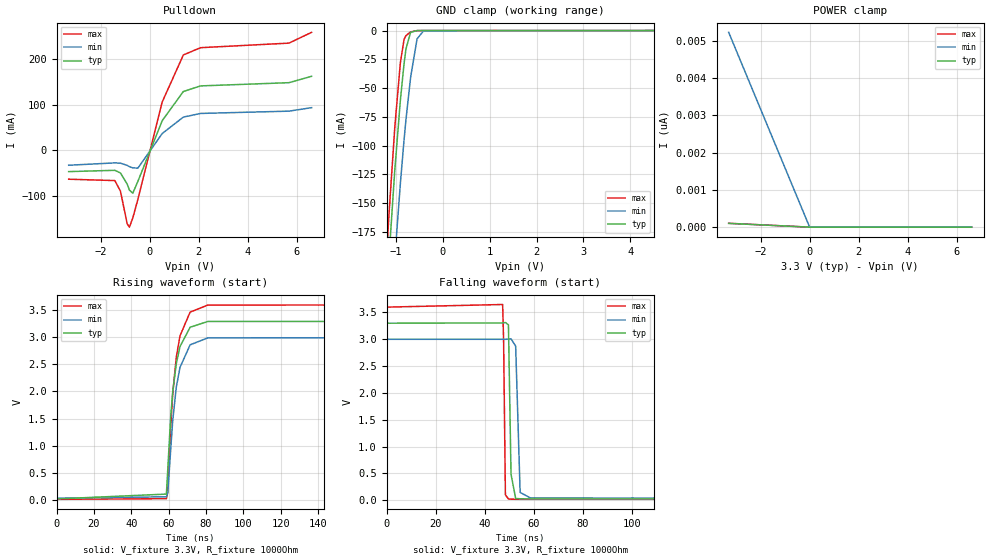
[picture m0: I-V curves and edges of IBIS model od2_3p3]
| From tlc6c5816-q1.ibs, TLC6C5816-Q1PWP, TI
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|   od2_3p3 Model
[Model]   od2_3p3
Model_type   Open_drain
Polarity   Inverting
Vmeas = 1.65
Vref = 3.3
Cref = 2pF
Rref = 1000
|   typ   min   max
C_comp   1.810pF   1.752pF   1.861pF
|  Where Nom  PVT is Nominal Process, 3.3V,  27C
|   Fast PVT is Strong Process,  3.6V, -40C
|   Slow PVT is Weak Process,   3.0V, 150C
[Voltage Range]   3.3   3   3.6
|Junction Temperature
[Temperature Range]   27   150   -40
[Pullup Reference]   3.3   3   3.6
[Pulldown Reference]   0   0   0
[Power Clamp Reference]   3.3   3   3.6
[GND Clamp Reference]   0   0   0
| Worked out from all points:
|   slope of the pulldown table from 0 to 0.495 V, typ, clamps not added: 7.82 ohm
|   GND clamp passes 1 mA (typ) near -0.67 V on its own axis
|   falling waveform, V_fixture 3.3V, R_fixture 1000Ohm: 20-80 % time 636ps typ, 954ps min, 498ps max; typ from 3.3 V to 0.022 V
|   rising waveform, V_fixture 3.3V, R_fixture 1000Ohm: 20-80 % time 5.13ns typ, 5.23ns min, 5.01ns max; typ from 0.022 V to 3.3 V
[Pulldown]
|   Voltage   I(typ)   I(min)   I(max)
-3.3V     -46.8mA    -32.81mA   -63.47mA
-1.419V   -43.95mA   -27.65mA   -66.49mA
-1.191V   -49.76mA   -28.24mA   -89.47mA
-914.1mV  -74.21mA   -33.12mA   -161.5mA
-825mV    -87.34mA   -35.88mA   -168.7mA
-686.4mV  -94.26mA   -38.61mA   -148.4mA
-478.5mV  -67.99mA   -39.11mA   -107.5mA
511.5mV   65.03mA    36.82mA    106mA
1.373V    129mA      72.82mA    209.2mA
2.076V    141.3mA    80.88mA    225.2mA
5.679V    148.4mA    85.9mA     235.2mA
6.6V      162.4mA    93.55mA    258.9mA
[GND Clamp]
|   Voltage   I(typ)   I(min)   I(max)
-3.3V     -1.761A    -1.722A    -1.8A
-1.27V    -279.8mA   -349.1mA   -245.5mA
-1.181V   -219.9mA   -293.1mA   -183mA
-1.142V   -194mA     -268.7mA   -156.3mA
-1.023V   -121.1mA   -197.8mA   -83.73mA
-904.2mV  -60.36mA   -132.7mA   -27.75mA
-825mV    -28.41mA   -94.54mA   -7.614mA
-785.4mV  -15.98mA   -77.47mA   -4.403mA
-686.4mV  -1.607mA   -40.73mA   -1.205mA
-547.8mV  -48.36uA   -7.215mA   -55.86uA
-409.2mV  -973.4nA   -268.1uA   -597.4nA
6.6V      0A         0A         0A
[POWER Clamp]
|   Voltage   I(typ)   I(min)   I(max)
-3.3V     101.7pA    5.233nA    103.6pA
0V        0A         0A         0A
6.6V      0A         0A         0A
[Ramp]
R_load = 1000
|   typ   min   max
dV/dt_r   1.96665/5.12977e-09   1.77859/5.23678e-09   2.15108/5.01039e-09
dV/dt_f   1.96665/6.35604e-10   1.77859/9.53702e-10   2.15108/4.98043e-10
[Falling Waveform]
V_fixture = 3.3V
V_fixture_min = 3V
V_fixture_max = 3.6V
R_fixture = 1000Ohm
C_fixture = 0F
|   Time   V(typ)   V(min)   V(max)
0s        3.3V       3V         3.6V
47.28ns   3.305V     3V         3.649V
47.67ns   3.307V     3V         2.97V
48.4ns    3.313V     3V         98.78mV
49.64ns   3.27V      3.005V     21.68mV
50.69ns   482.3mV    3.009V     17.49mV
52.58ns   31mV       2.872V     16.04mV
54.4ns    25.16mV    143.6mV    15.31mV
58.6ns    22.68mV    39.91mV    15.31mV
1.5us     22.26mV    35.67mV    14.87mV
[Rising Waveform]
V_fixture = 3.3V
V_fixture_min = 3V
V_fixture_max = 3.6V
R_fixture = 1000Ohm
C_fixture = 0F
|   Time   V(typ)   V(min)   V(max)
0s        22.26mV    35.67mV    14.87mV
58.8ns    111.2mV    61.5mV     26.86mV
59.54ns   567.5mV    131.8mV    155.6mV
61.05ns   1.507V     905.5mV    1.324V
62.2ns    1.996V     1.468V     1.96V
64.1ns    2.511V     2.077V     2.628V
66.07ns   2.825V     2.442V     3.022V
71.51ns   3.182V     2.858V     3.461V
81.04ns   3.288V     2.987V     3.59V
1.5us     3.3V       3V         3.6V
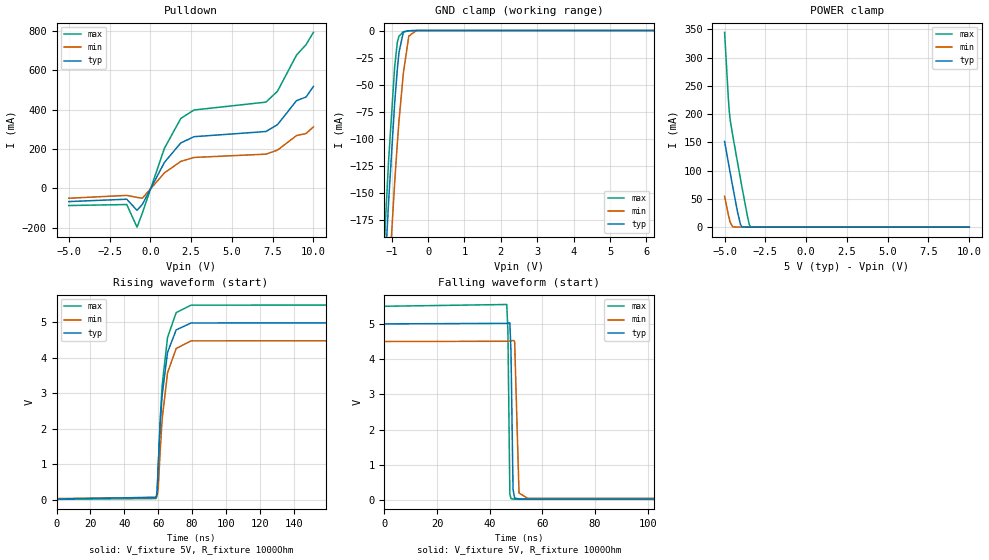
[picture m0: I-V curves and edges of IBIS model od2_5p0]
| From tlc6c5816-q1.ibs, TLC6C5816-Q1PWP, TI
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|   od2_5p0 Model
[Model]   od2_5p0
Model_type   Open_drain
Polarity   Inverting
Vmeas = 2.5
Vref = 5
Cref = 2pF
Rref = 1000
|   typ   min   max
C_comp   1.658pF   1.606pF   1.689pF
|  Where Nom  PVT is Nominal Process, 5.0V,  27C
|   Fast PVT is Strong Process,  5.5V, -40C
|   Slow PVT is Weak Process,   4.5V, 150C
[Voltage Range]   5   4.5   5.5
|Junction Temperature
[Temperature Range]   27   150   -40
[Pullup Reference]   5   4.5   5.5
[Pulldown Reference]   0   0   0
[Power Clamp Reference]   5   4.5   5.5
[GND Clamp Reference]   0   0   0
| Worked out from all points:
|   slope of the pulldown table from 0 to 0.75 V, typ, clamps not added: 6.47 ohm
|   GND clamp passes 1 mA (typ) near -0.63 V on its own axis
|   POWER clamp passes 1 mA (typ) near -3.97 V on its own axis
|   falling waveform, V_fixture 5V, R_fixture 1000Ohm: 20-80 % time 571ps typ, 765ps min, 490ps max; typ from 5 V to 0.028 V
|   rising waveform, V_fixture 5V, R_fixture 1000Ohm: 20-80 % time 4.85ns typ, 4.94ns min, 4.75ns max; typ from 0.028 V to 5 V
[Pulldown]
|   Voltage   I(typ)   I(min)   I(max)
-5V       -66.87mA   -49.94mA   -86.91mA
-1.445V   -54.85mA   -35.44mA   -81.86mA
-815mV    -111.3mA   -45.79mA   -196.8mA
-485mV    -80.91mA   -49.64mA   -124.6mA
865mV     132.3mA    78.96mA    203.9mA
1.87V     231.3mA    137.4mA    355.6mA
2.68V     262.8mA    157.3mA    398.4mA
7.09V     289.2mA    174.2mA    438.5mA
7.795V    324mA      194.6mA    493.7mA
8.965V    446.1mA    268.6mA    677.7mA
9.55V     464.4mA    279mA      730.8mA
10V       518.3mA    312.8mA    793.1mA
[GND Clamp]
|   Voltage   I(typ)   I(min)   I(max)
-5V       -3.029A    -2.902A    -3.125A
-1.415V   -380.1mA   -442.1mA   -350.9mA
-1.25V    -265.9mA   -336.1mA   -230.9mA
-1.16V    -205.8mA   -279.9mA   -168.4mA
-1.085V   -158.1mA   -234.3mA   -119.9mA
-920mV    -67.6mA    -141.1mA   -33.95mA
-845mV    -35.72mA   -103.9mA   -10.67mA
-800mV    -20.2mA    -83.6mA    -5.294mA
-680mV    -1.359mA   -39.34mA   -1.085mA
-530mV    -238uA     -5.095mA   -192.6uA
-320mV    -8.778uA   -24.45uA   -9.031uA
10V       0A         0A         0A
[POWER Clamp]
|   Voltage   I(typ)   I(min)   I(max)
-5V       151.6mA    54.59mA    344.6mA
-4.775V   115.2mA    22.48mA    230mA
-4.715V   105.6mA    14.96mA    205.6mA
-4.655V   96.03mA    8.438mA    188.9mA
-4.505V   72.26mA    508.5uA    163mA
-4.22V    28.73mA    191nA      116.6mA
-4.025V   4.362mA    0A         85.14mA
-3.92V    197.7uA    0A         68.38mA
-3.59V    0A         0A         17.87mA
-3.485V   0A         0A         4.783mA
-3.41V    0A         0A         420.9uA
10V       0A         0A         0A
[Ramp]
R_load = 1000
|   typ   min   max
dV/dt_r   2.98328/4.85844e-09   2.6749/4.94065e-09   3.28809/4.75111e-09
dV/dt_f   2.98328/5.71232e-10   2.6749/7.64588e-10   3.28809/4.89988e-10
[Falling Waveform]
V_fixture = 5V
V_fixture_min = 4.5V
V_fixture_max = 5.5V
R_fixture = 1000Ohm
C_fixture = 0F
|   Time   V(typ)   V(min)   V(max)
0s        5V         4.5V       5.5V
46.46ns   5.015V     4.506V     5.55V
46.9ns    5.023V     4.508V     4.801V
47.64ns   5.03V      4.51V      167.8mV
48.07ns   4.209V     4.513V     40.88mV
48.85ns   307.1mV    4.531V     27.03mV
49.45ns   54.49mV    4.507V     23.53mV
51.12ns   33.88mV    200mV      21.67mV
54.39ns   28.88mV    47.92mV    20.45mV
1.5us     27.87mV    41.82mV    19.85mV
[Rising Waveform]
V_fixture = 5V
V_fixture_min = 4.5V
V_fixture_max = 5.5V
R_fixture = 1000Ohm
C_fixture = 0F
|   Time   V(typ)   V(min)   V(max)
0s        27.87mV    41.82mV    19.85mV
58.81ns   77.34mV    72.08mV    43.41mV
59.39ns   249.3mV    121.4mV    156.3mV
60.05ns   963.7mV    329.6mV    925.8mV
61.17ns   2.099V     1.351V     2.239V
62.37ns   2.959V     2.278V     3.225V
65.56ns   4.156V     3.582V     4.576V
70.66ns   4.787V     4.263V     5.273V
79.46ns   4.98V      4.478V     5.482V
1.5us     5V         4.5V       5.5V
